VERSION 5.8 ;
NAMESCASESENSITIVE ON ;
BUSBITCHARS "[]" ;
DIVIDERCHAR "/" ;
UNITS
  DATABASE MICRONS 1000 ;
END UNITS

-- Layer definitions (adjust according to your PDK)
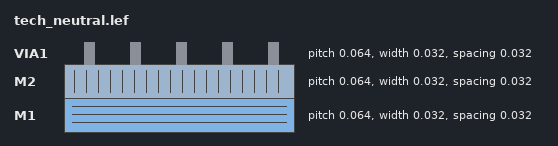
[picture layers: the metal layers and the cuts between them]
LAYER M1
  TYPE ROUTING ;
  DIRECTION HORIZONTAL ;
  PITCH 0.064 ;
  WIDTH 0.032 ;
  SPACING 0.032 ;
  OFFSET 0.032 ;
END M1

LAYER M2
  TYPE ROUTING ;
  DIRECTION VERTICAL ;
  PITCH 0.064 ;
  WIDTH 0.032 ;
  SPACING 0.032 ;
  OFFSET 0.032 ;
END M2

LAYER VIA1
  TYPE CUT ;
  PITCH 0.064 0.064 ;
  WIDTH 0.032 ;
  SPACING 0.032 ;
END VIA1

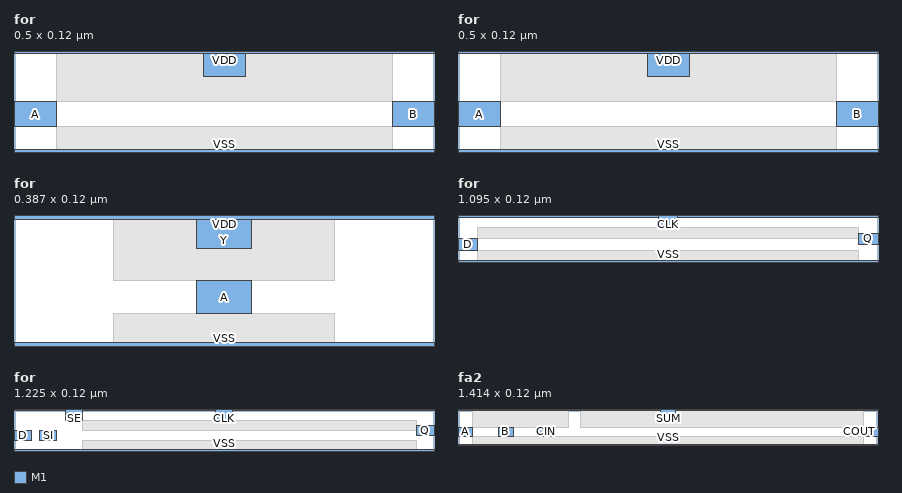
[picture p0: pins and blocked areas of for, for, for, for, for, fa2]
-- Macro for nor2 with power rails and MY symmetry
MACRO nor2
  CLASS CORE ;
  ORIGIN 0.0 0.0 ;
  SIZE 0.5 BY 0.12 ;
  SYMMETRY MY ;
  PIN A
    DIRECTION INPUT ;
    USE SIGNAL ;
    PORT
      LAYER M1 ;
      RECT 0.0 0.03 0.05 0.06 ;
    END
  END A
  PIN B
    DIRECTION INPUT ;
    USE SIGNAL ;
    PORT
      LAYER M1 ;
      RECT 0.45 0.03 0.5 0.06 ;
    END
  END B
  PIN Y
    DIRECTION OUTPUT ;
    USE SIGNAL ;
    PORT
      LAYER M1 ;
      RECT 0.225 0.09 0.275 0.12 ;
    END
  END Y
  PIN VDD
    DIRECTION INOUT ;
    USE POWER ;
    PORT
      LAYER M1 ;
      RECT 0.0 0.117 0.5 0.12 ;
    END
  END VDD
  PIN VSS
    DIRECTION INOUT ;
    USE GROUND ;
    PORT
      LAYER M1 ;
      RECT 0.0 0.0 0.5 0.003 ;
    END
  END VSS
  OBS
    LAYER M1 ;
    RECT 0.05 0.003 0.45 0.03 ;
    RECT 0.05 0.06 0.45 0.117 ;
  END
END nor2

-- Macro for nand2 with power rails and MY symmetry
MACRO nand2
  CLASS CORE ;
  ORIGIN 0.0 0.0 ;
  SIZE 0.5 BY 0.12 ;
  SYMMETRY MY ;
  PIN A
    DIRECTION INPUT ;
    USE SIGNAL ;
    PORT
      LAYER M1 ;
      RECT 0.0 0.03 0.05 0.06 ;
    END
  END A
  PIN B
    DIRECTION INPUT ;
    USE SIGNAL ;
    PORT
      LAYER M1 ;
      RECT 0.45 0.03 0.5 0.06 ;
    END
  END B
  PIN Y
    DIRECTION OUTPUT ;
    USE SIGNAL ;
    PORT
      LAYER M1 ;
      RECT 0.225 0.09 0.275 0.12 ;
    END
  END Y
  PIN VDD
    DIRECTION INOUT ;
    USE POWER ;
    PORT
      LAYER M1 ;
      RECT 0.0 0.117 0.5 0.12 ;
    END
  END VDD
  PIN VSS
    DIRECTION INOUT ;
    USE GROUND ;
    PORT
      LAYER M1 ;
      RECT 0.0 0.0 0.5 0.003 ;
    END
  END VSS
  OBS
    LAYER M1 ;
    RECT 0.05 0.003 0.45 0.03 ;
    RECT 0.05 0.06 0.45 0.117 ;
  END
END nand2

-- Macro for inv with power rails and MY symmetry
MACRO inv
  CLASS CORE ;
  ORIGIN 0.0 0.0 ;
  SIZE 0.387 BY 0.12 ;
  SYMMETRY MY ;
  PIN A
    DIRECTION INPUT ;
    USE SIGNAL ;
    PORT
      LAYER M1 ;
      RECT 0.1685 0.03 0.2185 0.06 ;
    END
  END A
  PIN Y
    DIRECTION OUTPUT ;
    USE SIGNAL ;
    PORT
      LAYER M1 ;
      RECT 0.1685 0.09 0.2185 0.12 ;
    END
  END Y
  PIN VDD
    DIRECTION INOUT ;
    USE POWER ;
    PORT
      LAYER M1 ;
      RECT 0.0 0.117 0.387 0.12 ;
    END
  END VDD
  PIN VSS
    DIRECTION INOUT ;
    USE GROUND ;
    PORT
      LAYER M1 ;
      RECT 0.0 0.0 0.387 0.003 ;
    END
  END VSS
  OBS
    LAYER M1 ;
    RECT 0.0915 0.003 0.2955 0.03 ;
    RECT 0.0915 0.06 0.2955 0.117 ;
  END
END inv

-- Macro for dflop with power rails and MY symmetry
MACRO dflop
  CLASS SEQUENTIAL ;
  ORIGIN 0.0 0.0 ;
  SIZE 1.095 BY 0.12 ;
  SYMMETRY MY ;
  PIN D
    DIRECTION INPUT ;
    USE SIGNAL ;
    PORT
      LAYER M1 ;
      RECT 0.0 0.03 0.05 0.06 ;
    END
  END D
  PIN CLK
    DIRECTION INPUT ;
    USE SIGNAL ;
    PORT
      LAYER M1 ;
      RECT 0.5225 0.09 0.5725 0.12 ;
    END
  END CLK
  PIN Q
    DIRECTION OUTPUT ;
    USE SIGNAL ;
    PORT
      LAYER M1 ;
      RECT 1.045 0.045 1.095 0.075 ;
    END
  END Q
  PIN VDD
    DIRECTION INOUT ;
    USE POWER ;
    PORT
      LAYER M1 ;
      RECT 0.0 0.117 1.095 0.12 ;
    END
  END VDD
  PIN VSS
    DIRECTION INOUT ;
    USE GROUND ;
    PORT
      LAYER M1 ;
      RECT 0.0 0.0 1.095 0.003 ;
    END
  END VSS
  OBS
    LAYER M1 ;
    RECT 0.05 0.003 1.045 0.03 ;
    RECT 0.05 0.06 1.045 0.09 ;
  END
END dflop

-- Macro for sdflop with power rails and MY symmetry
MACRO sdflop
  CLASS SEQUENTIAL ;
  ORIGIN 0.0 0.0 ;
  SIZE 1.225 BY 0.12 ;
  SYMMETRY MY ;
  PIN D
    DIRECTION INPUT ;
    USE SIGNAL ;
    PORT
      LAYER M1 ;
      RECT 0.0 0.03 0.05 0.06 ;
    END
  END D
  PIN SI
    DIRECTION INPUT ;
    USE SIGNAL ;
    PORT
      LAYER M1 ;
      RECT 0.075 0.03 0.125 0.06 ;
    END
  END SI
  PIN SE
    DIRECTION INPUT ;
    USE SIGNAL ;
    PORT
      LAYER M1 ;
      RECT 0.15 0.09 0.2 0.12 ;
    END
  END SE
  PIN CLK
    DIRECTION INPUT ;
    USE SIGNAL ;
    PORT
      LAYER M1 ;
      RECT 0.5875 0.09 0.6375 0.12 ;
    END
  END CLK
  PIN Q
    DIRECTION OUTPUT ;
    USE SIGNAL ;
    PORT
      LAYER M1 ;
      RECT 1.175 0.045 1.225 0.075 ;
    END
  END Q
  PIN VDD
    DIRECTION INOUT ;
    USE POWER ;
    PORT
      LAYER M1 ;
      RECT 0.0 0.117 1.225 0.12 ;
    END
  END VDD
  PIN VSS
    DIRECTION INOUT ;
    USE GROUND ;
    PORT
      LAYER M1 ;
      RECT 0.0 0.0 1.225 0.003 ;
    END
  END VSS
  OBS
    LAYER M1 ;
    RECT 0.2 0.003 1.175 0.03 ;
    RECT 0.2 0.06 1.175 0.09 ;
  END
END sdflop

-- Repeat the same pattern for all other cells (fa2, mux2, mux3, mux4, xor2, nand3, nand4, or2, or3, icg)
-- Example for fa2:
MACRO fa2
  CLASS CORE ;
  ORIGIN 0.0 0.0 ;
  SIZE 1.414 BY 0.12 ;
  SYMMETRY MY ;
  PIN A
    DIRECTION INPUT ;
    USE SIGNAL ;
    PORT
      LAYER M1 ;
      RECT 0.0 0.03 0.05 0.06 ;
    END
  END A
  PIN B
    DIRECTION INPUT ;
    USE SIGNAL ;
    PORT
      LAYER M1 ;
      RECT 0.136 0.03 0.186 0.06 ;
    END
  END B
  PIN CIN
    DIRECTION INPUT ;
    USE SIGNAL ;
    PORT
      LAYER M1 ;
      RECT 0.272 0.03 0.322 0.06 ;
    END
  END CIN
  PIN SUM
    DIRECTION OUTPUT ;
    USE SIGNAL ;
    PORT
      LAYER M1 ;
      RECT 0.682 0.09 0.732 0.12 ;
    END
  END SUM
  PIN COUT
    DIRECTION OUTPUT ;
    USE SIGNAL ;
    PORT
      LAYER M1 ;
      RECT 1.364 0.03 1.414 0.06 ;
    END
  END COUT
  PIN VDD
    DIRECTION INOUT ;
    USE POWER ;
    PORT
      LAYER M1 ;
      RECT 0.0 0.117 1.414 0.12 ;
    END
  END VDD
  PIN VSS
    DIRECTION INOUT ;
    USE GROUND ;
    PORT
      LAYER M1 ;
      RECT 0.0 0.0 1.414 0.003 ;
    END
  END VSS
  OBS
    LAYER M1 ;
    RECT 0.05 0.003 1.364 0.03 ;
    RECT 0.05 0.06 0.372 0.117 ;
    RECT 0.412 0.06 1.364 0.117 ;
  END
END fa2
